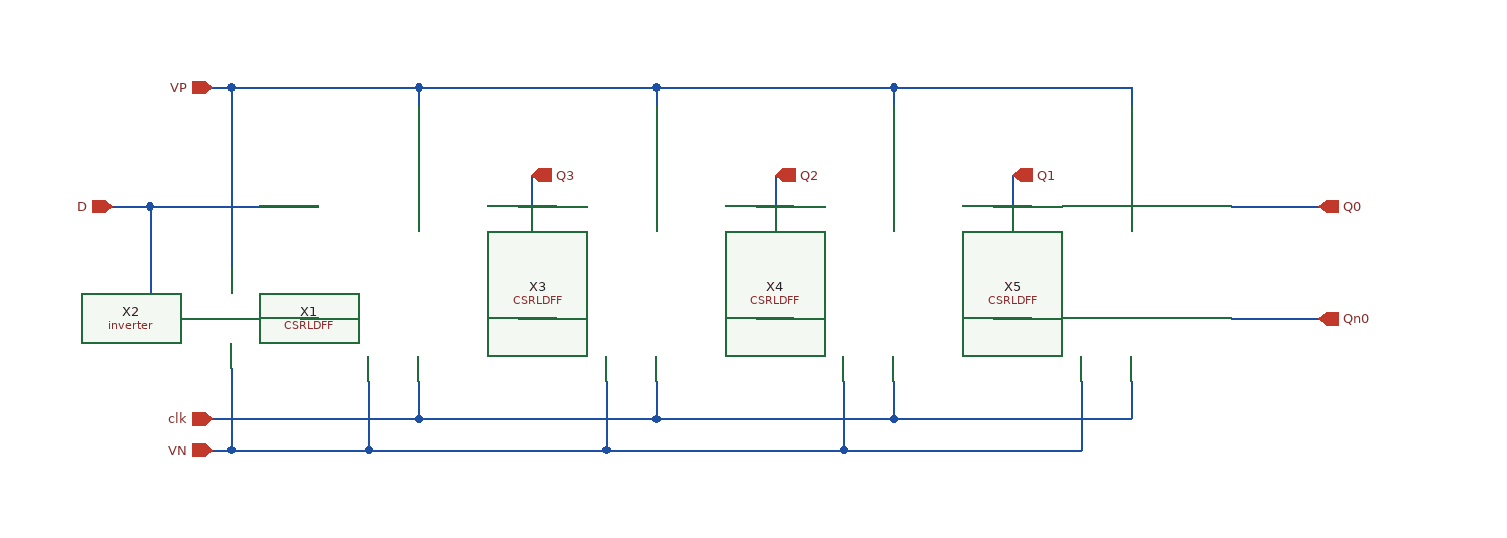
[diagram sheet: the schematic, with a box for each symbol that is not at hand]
v {xschem version=2.9.9 file_version=1.2 }
G {}
K {}
V {}
S {}
E {}
N 385 -210 400 -210 { lab=#net1}
N 265 -210 290 -210 { lab=D}
N 265 -300 265 -210 { lab=D}
N 265 -300 400 -300 { lab=D}
N 235 -300 265 -300 { lab=D}
N 315 -130 480 -130 { lab=clk}
N 480 -160 480 -130 { lab=clk}
N 1130 -300 1200 -300 { lab=Q0}
N 1130 -210 1200 -210 { lab=Qn0}
N 670 -160 670 -130 { lab=clk}
N 860 -160 860 -130 { lab=clk}
N 1050 -160 1050 -130 { lab=clk}
N 940 -300 970 -300 { lab=Q1}
N 750 -300 780 -300 { lab=Q2}
N 560 -300 590 -300 { lab=Q3}
N 480 -130 670 -130 { lab=clk}
N 670 -130 860 -130 { lab=clk}
N 860 -130 1050 -130 { lab=clk}
N 560 -210 590 -210 { lab=#net2}
N 750 -210 780 -210 { lab=#net3}
N 940 -210 970 -210 { lab=#net4}
N 330 -165 330 -105 { lab=VN}
N 315 -105 330 -105 { lab=VN}
N 330 -105 440 -105 { lab=VN}
N 440 -160 440 -105 { lab=VN}
N 440 -105 630 -105 { lab=VN}
N 630 -160 630 -105 { lab=VN}
N 630 -105 820 -105 { lab=VN}
N 820 -160 820 -105 { lab=VN}
N 820 -105 1010 -105 { lab=VN}
N 1010 -160 1010 -105 { lab=VN}
N 330 -395 330 -250 { lab=VP}
N 315 -395 330 -395 { lab=VP}
N 330 -395 480 -395 { lab=VP}
N 480 -395 480 -380 { lab=VP}
N 480 -395 670 -395 { lab=VP}
N 670 -395 670 -380 { lab=VP}
N 670 -395 860 -395 { lab=VP}
N 860 -395 860 -380 { lab=VP}
N 860 -395 1045 -395 { lab=VP}
N 1045 -395 1050 -395 { lab=VP}
N 1050 -395 1050 -380 { lab=VP}
N 570 -325 570 -300 { lab=Q3}
N 765 -325 765 -300 { lab=Q2}
N 955 -325 955 -300 { lab=Q1}
N 330 -170 330 -165 { lab=VN}
C {/home/madvlsi/Desktop/MAD_VLSI/MiniProject2-CSRLDFF/XSCHEM/CSRLDFF.sym} 320 -200 0 0 {name=X1}
C {/home/madvlsi/Desktop/MAD_VLSI/MiniProject2-CSRLDFF/XSCHEM/inverter.sym} 250 -210 0 0 {name = X2}
C {/home/madvlsi/Desktop/MAD_VLSI/MiniProject2-CSRLDFF/XSCHEM/CSRLDFF.sym} 510 -200 0 0 {name=X3}
C {/home/madvlsi/Desktop/MAD_VLSI/MiniProject2-CSRLDFF/XSCHEM/CSRLDFF.sym} 700 -200 0 0 {name=X4}
C {/home/madvlsi/Desktop/MAD_VLSI/MiniProject2-CSRLDFF/XSCHEM/CSRLDFF.sym} 890 -200 0 0 {name=X5}
C {devices/opin.sym} 1200 -300 0 0 {name=p1 lab=Q0}
C {devices/opin.sym} 1200 -210 0 0 {name=p2 lab=Qn0}
C {devices/opin.sym} 955 -325 3 0 {name=p3 lab=Q1}
C {devices/opin.sym} 765 -325 3 0 {name=p4 lab=Q2}
C {devices/opin.sym} 570 -325 3 0 {name=p5 lab=Q3}
C {devices/ipin.sym} 235 -300 0 0 {name=p6 lab=D}
C {devices/ipin.sym} 315 -130 0 0 {name=p7 lab=clk}
C {devices/iopin.sym} 315 -395 2 0 {name=p8 lab=VP}
C {devices/iopin.sym} 315 -105 2 0 {name=p9 lab=VN}
